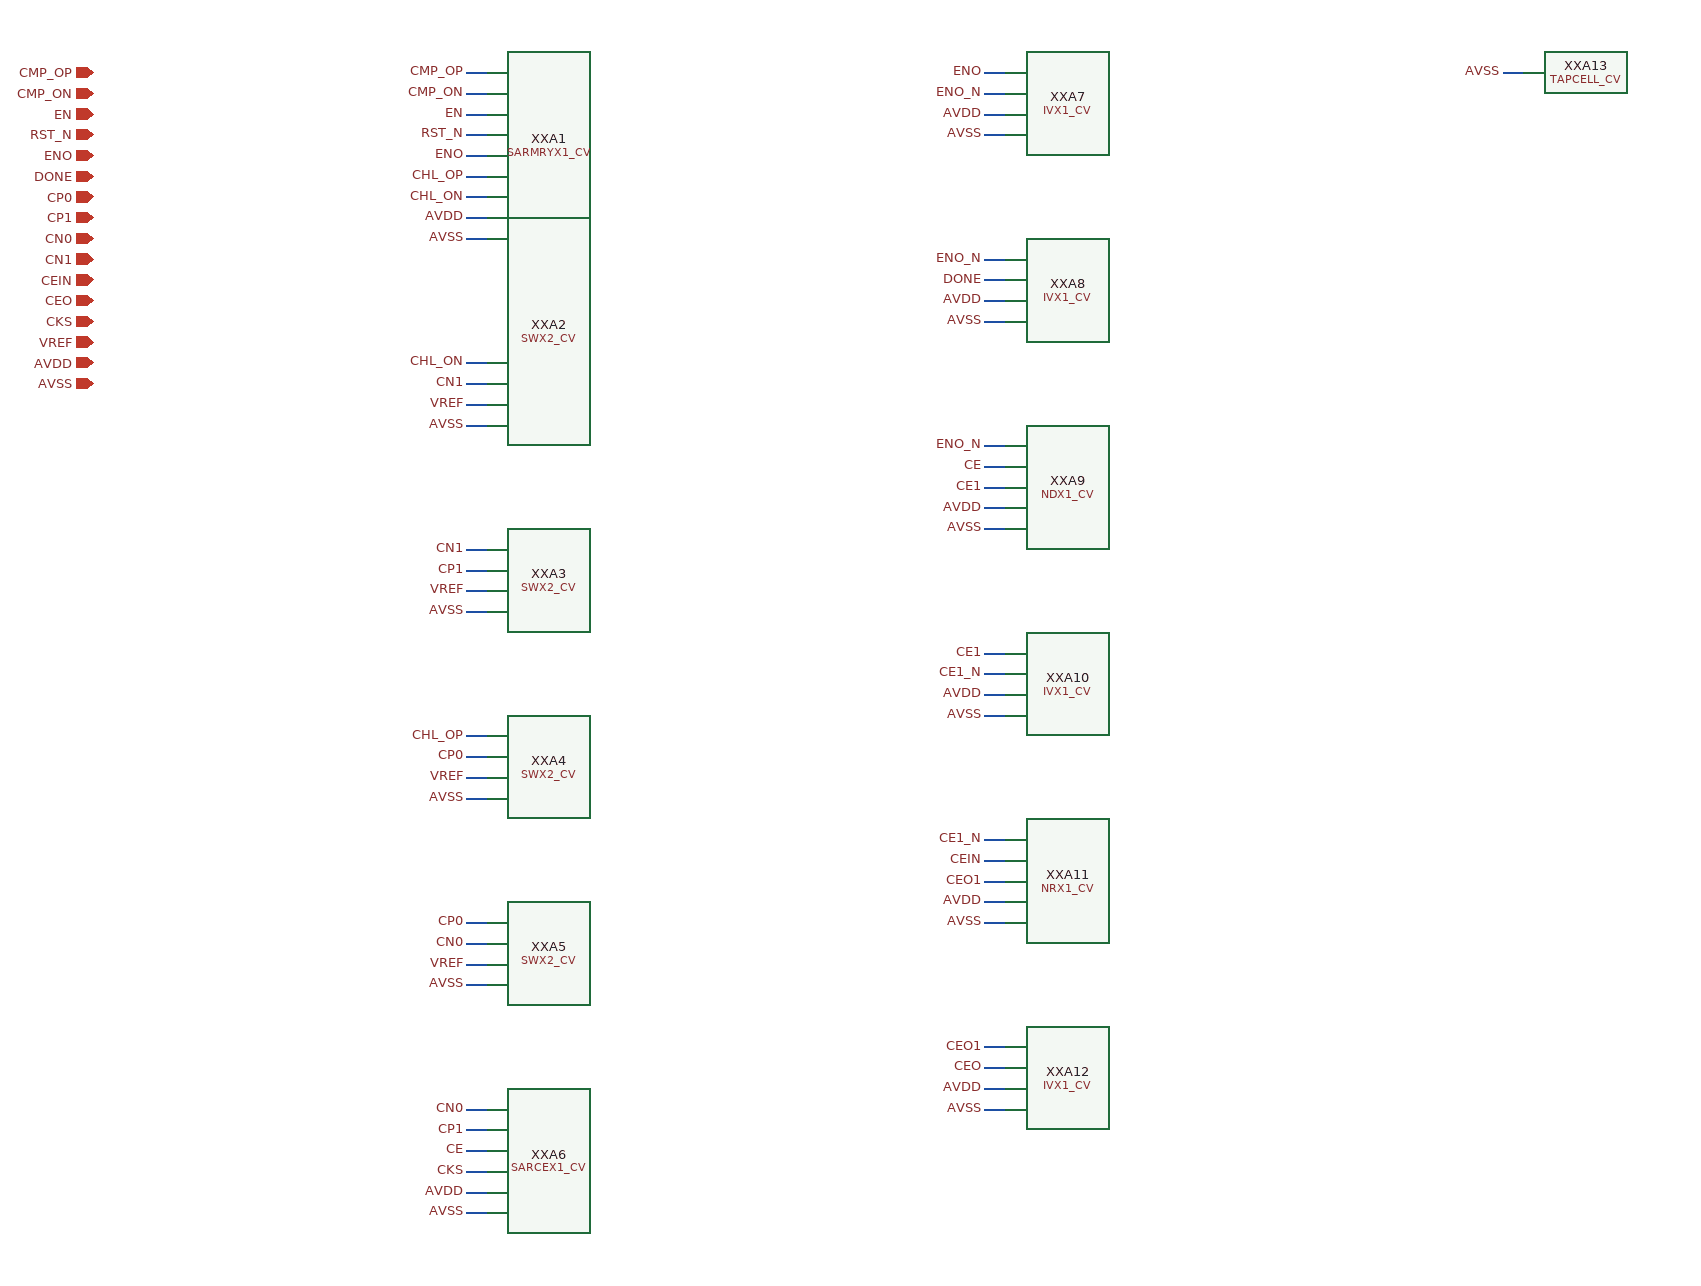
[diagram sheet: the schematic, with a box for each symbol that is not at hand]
v {xschem version=3.0.0 file_version=1.2 }
G {}
K {}
V {}
S {}
E {}
C {devices/iopin.sym} 0 0 0 0 {name=p0 lab=CMP_OP}
C {devices/iopin.sym} 0 20 0 0 {name=p1 lab=CMP_ON}
C {devices/iopin.sym} 0 40 0 0 {name=p2 lab=EN}
C {devices/iopin.sym} 0 60 0 0 {name=p3 lab=RST_N}
C {devices/iopin.sym} 0 80 0 0 {name=p4 lab=ENO}
C {devices/iopin.sym} 0 100 0 0 {name=p5 lab=DONE}
C {devices/iopin.sym} 0 120 0 0 {name=p6 lab=CP0}
C {devices/iopin.sym} 0 140 0 0 {name=p7 lab=CP1}
C {devices/iopin.sym} 0 160 0 0 {name=p8 lab=CN0}
C {devices/iopin.sym} 0 180 0 0 {name=p9 lab=CN1}
C {devices/iopin.sym} 0 200 0 0 {name=p10 lab=CEIN}
C {devices/iopin.sym} 0 220 0 0 {name=p11 lab=CEO}
C {devices/iopin.sym} 0 240 0 0 {name=p12 lab=CKS}
C {devices/iopin.sym} 0 260 0 0 {name=p13 lab=VREF}
C {devices/iopin.sym} 0 280 0 0 {name=p14 lab=AVDD}
C {devices/iopin.sym} 0 300 0 0 {name=p15 lab=AVSS}
C {SAR9B/SARMRYX1_CV.sym} 400 0 0 0 {name=XXA1}
N 360.0 0.0 380.0 0.0 {lab=CMP_OP}
C {devices/lab_pin.sym} 360.0 0.0 0 0 {name=l0 sig_type=std_logic lab=CMP_OP }
N 360.0 20.0 380.0 20.0 {lab=CMP_ON}
C {devices/lab_pin.sym} 360.0 20.0 0 0 {name=l1 sig_type=std_logic lab=CMP_ON }
N 360.0 40.0 380.0 40.0 {lab=EN}
C {devices/lab_pin.sym} 360.0 40.0 0 0 {name=l2 sig_type=std_logic lab=EN }
N 360.0 60.0 380.0 60.0 {lab=RST_N}
C {devices/lab_pin.sym} 360.0 60.0 0 0 {name=l3 sig_type=std_logic lab=RST_N }
N 360.0 80.0 380.0 80.0 {lab=ENO}
C {devices/lab_pin.sym} 360.0 80.0 0 0 {name=l4 sig_type=std_logic lab=ENO }
N 360.0 100.0 380.0 100.0 {lab=CHL_OP}
C {devices/lab_pin.sym} 360.0 100.0 0 0 {name=l5 sig_type=std_logic lab=CHL_OP }
N 360.0 120.0 380.0 120.0 {lab=CHL_ON}
C {devices/lab_pin.sym} 360.0 120.0 0 0 {name=l6 sig_type=std_logic lab=CHL_ON }
N 360.0 140.0 380.0 140.0 {lab=AVDD}
C {devices/lab_pin.sym} 360.0 140.0 0 0 {name=l7 sig_type=std_logic lab=AVDD }
N 360.0 160.0 380.0 160.0 {lab=AVSS}
C {devices/lab_pin.sym} 360.0 160.0 0 0 {name=l8 sig_type=std_logic lab=AVSS }
C {SAR9B/SWX2_CV.sym} 400 280.0 0 0 {name=XXA2}
N 360.0 280.0 380.0 280.0 {lab=CHL_ON}
C {devices/lab_pin.sym} 360.0 280.0 0 0 {name=l9 sig_type=std_logic lab=CHL_ON }
N 360.0 300.0 380.0 300.0 {lab=CN1}
C {devices/lab_pin.sym} 360.0 300.0 0 0 {name=l10 sig_type=std_logic lab=CN1 }
N 360.0 320.0 380.0 320.0 {lab=VREF}
C {devices/lab_pin.sym} 360.0 320.0 0 0 {name=l11 sig_type=std_logic lab=VREF }
N 360.0 340.0 380.0 340.0 {lab=AVSS}
C {devices/lab_pin.sym} 360.0 340.0 0 0 {name=l12 sig_type=std_logic lab=AVSS }
C {SAR9B/SWX2_CV.sym} 400 460.0 0 0 {name=XXA3}
N 360.0 460.0 380.0 460.0 {lab=CN1}
C {devices/lab_pin.sym} 360.0 460.0 0 0 {name=l13 sig_type=std_logic lab=CN1 }
N 360.0 480.0 380.0 480.0 {lab=CP1}
C {devices/lab_pin.sym} 360.0 480.0 0 0 {name=l14 sig_type=std_logic lab=CP1 }
N 360.0 500.0 380.0 500.0 {lab=VREF}
C {devices/lab_pin.sym} 360.0 500.0 0 0 {name=l15 sig_type=std_logic lab=VREF }
N 360.0 520.0 380.0 520.0 {lab=AVSS}
C {devices/lab_pin.sym} 360.0 520.0 0 0 {name=l16 sig_type=std_logic lab=AVSS }
C {SAR9B/SWX2_CV.sym} 400 640.0 0 0 {name=XXA4}
N 360.0 640.0 380.0 640.0 {lab=CHL_OP}
C {devices/lab_pin.sym} 360.0 640.0 0 0 {name=l17 sig_type=std_logic lab=CHL_OP }
N 360.0 660.0 380.0 660.0 {lab=CP0}
C {devices/lab_pin.sym} 360.0 660.0 0 0 {name=l18 sig_type=std_logic lab=CP0 }
N 360.0 680.0 380.0 680.0 {lab=VREF}
C {devices/lab_pin.sym} 360.0 680.0 0 0 {name=l19 sig_type=std_logic lab=VREF }
N 360.0 700.0 380.0 700.0 {lab=AVSS}
C {devices/lab_pin.sym} 360.0 700.0 0 0 {name=l20 sig_type=std_logic lab=AVSS }
C {SAR9B/SWX2_CV.sym} 400 820.0 0 0 {name=XXA5}
N 360.0 820.0 380.0 820.0 {lab=CP0}
C {devices/lab_pin.sym} 360.0 820.0 0 0 {name=l21 sig_type=std_logic lab=CP0 }
N 360.0 840.0 380.0 840.0 {lab=CN0}
C {devices/lab_pin.sym} 360.0 840.0 0 0 {name=l22 sig_type=std_logic lab=CN0 }
N 360.0 860.0 380.0 860.0 {lab=VREF}
C {devices/lab_pin.sym} 360.0 860.0 0 0 {name=l23 sig_type=std_logic lab=VREF }
N 360.0 880.0 380.0 880.0 {lab=AVSS}
C {devices/lab_pin.sym} 360.0 880.0 0 0 {name=l24 sig_type=std_logic lab=AVSS }
C {SAR9B/SARCEX1_CV.sym} 400 1000.0 0 0 {name=XXA6}
N 360.0 1000.0 380.0 1000.0 {lab=CN0}
C {devices/lab_pin.sym} 360.0 1000.0 0 0 {name=l25 sig_type=std_logic lab=CN0 }
N 360.0 1020.0 380.0 1020.0 {lab=CP1}
C {devices/lab_pin.sym} 360.0 1020.0 0 0 {name=l26 sig_type=std_logic lab=CP1 }
N 360.0 1040.0 380.0 1040.0 {lab=CE}
C {devices/lab_pin.sym} 360.0 1040.0 0 0 {name=l27 sig_type=std_logic lab=CE }
N 360.0 1060.0 380.0 1060.0 {lab=CKS}
C {devices/lab_pin.sym} 360.0 1060.0 0 0 {name=l28 sig_type=std_logic lab=CKS }
N 360.0 1080.0 380.0 1080.0 {lab=AVDD}
C {devices/lab_pin.sym} 360.0 1080.0 0 0 {name=l29 sig_type=std_logic lab=AVDD }
N 360.0 1100.0 380.0 1100.0 {lab=AVSS}
C {devices/lab_pin.sym} 360.0 1100.0 0 0 {name=l30 sig_type=std_logic lab=AVSS }
C {SAR9B/IVX1_CV.sym} 900 0 0 0 {name=XXA7}
N 860.0 0.0 880.0 0.0 {lab=ENO}
C {devices/lab_pin.sym} 860.0 0.0 0 0 {name=l31 sig_type=std_logic lab=ENO }
N 860.0 20.0 880.0 20.0 {lab=ENO_N}
C {devices/lab_pin.sym} 860.0 20.0 0 0 {name=l32 sig_type=std_logic lab=ENO_N }
N 860.0 40.0 880.0 40.0 {lab=AVDD}
C {devices/lab_pin.sym} 860.0 40.0 0 0 {name=l33 sig_type=std_logic lab=AVDD }
N 860.0 60.0 880.0 60.0 {lab=AVSS}
C {devices/lab_pin.sym} 860.0 60.0 0 0 {name=l34 sig_type=std_logic lab=AVSS }
C {SAR9B/IVX1_CV.sym} 900 180.0 0 0 {name=XXA8}
N 860.0 180.0 880.0 180.0 {lab=ENO_N}
C {devices/lab_pin.sym} 860.0 180.0 0 0 {name=l35 sig_type=std_logic lab=ENO_N }
N 860.0 200.0 880.0 200.0 {lab=DONE}
C {devices/lab_pin.sym} 860.0 200.0 0 0 {name=l36 sig_type=std_logic lab=DONE }
N 860.0 220.0 880.0 220.0 {lab=AVDD}
C {devices/lab_pin.sym} 860.0 220.0 0 0 {name=l37 sig_type=std_logic lab=AVDD }
N 860.0 240.0 880.0 240.0 {lab=AVSS}
C {devices/lab_pin.sym} 860.0 240.0 0 0 {name=l38 sig_type=std_logic lab=AVSS }
C {SAR9B/NDX1_CV.sym} 900 360.0 0 0 {name=XXA9}
N 860.0 360.0 880.0 360.0 {lab=ENO_N}
C {devices/lab_pin.sym} 860.0 360.0 0 0 {name=l39 sig_type=std_logic lab=ENO_N }
N 860.0 380.0 880.0 380.0 {lab=CE}
C {devices/lab_pin.sym} 860.0 380.0 0 0 {name=l40 sig_type=std_logic lab=CE }
N 860.0 400.0 880.0 400.0 {lab=CE1}
C {devices/lab_pin.sym} 860.0 400.0 0 0 {name=l41 sig_type=std_logic lab=CE1 }
N 860.0 420.0 880.0 420.0 {lab=AVDD}
C {devices/lab_pin.sym} 860.0 420.0 0 0 {name=l42 sig_type=std_logic lab=AVDD }
N 860.0 440.0 880.0 440.0 {lab=AVSS}
C {devices/lab_pin.sym} 860.0 440.0 0 0 {name=l43 sig_type=std_logic lab=AVSS }
C {SAR9B/IVX1_CV.sym} 900 560.0 0 0 {name=XXA10}
N 860.0 560.0 880.0 560.0 {lab=CE1}
C {devices/lab_pin.sym} 860.0 560.0 0 0 {name=l44 sig_type=std_logic lab=CE1 }
N 860.0 580.0 880.0 580.0 {lab=CE1_N}
C {devices/lab_pin.sym} 860.0 580.0 0 0 {name=l45 sig_type=std_logic lab=CE1_N }
N 860.0 600.0 880.0 600.0 {lab=AVDD}
C {devices/lab_pin.sym} 860.0 600.0 0 0 {name=l46 sig_type=std_logic lab=AVDD }
N 860.0 620.0 880.0 620.0 {lab=AVSS}
C {devices/lab_pin.sym} 860.0 620.0 0 0 {name=l47 sig_type=std_logic lab=AVSS }
C {SAR9B/NRX1_CV.sym} 900 740.0 0 0 {name=XXA11}
N 860.0 740.0 880.0 740.0 {lab=CE1_N}
C {devices/lab_pin.sym} 860.0 740.0 0 0 {name=l48 sig_type=std_logic lab=CE1_N }
N 860.0 760.0 880.0 760.0 {lab=CEIN}
C {devices/lab_pin.sym} 860.0 760.0 0 0 {name=l49 sig_type=std_logic lab=CEIN }
N 860.0 780.0 880.0 780.0 {lab=CEO1}
C {devices/lab_pin.sym} 860.0 780.0 0 0 {name=l50 sig_type=std_logic lab=CEO1 }
N 860.0 800.0 880.0 800.0 {lab=AVDD}
C {devices/lab_pin.sym} 860.0 800.0 0 0 {name=l51 sig_type=std_logic lab=AVDD }
N 860.0 820.0 880.0 820.0 {lab=AVSS}
C {devices/lab_pin.sym} 860.0 820.0 0 0 {name=l52 sig_type=std_logic lab=AVSS }
C {SAR9B/IVX1_CV.sym} 900 940.0 0 0 {name=XXA12}
N 860.0 940.0 880.0 940.0 {lab=CEO1}
C {devices/lab_pin.sym} 860.0 940.0 0 0 {name=l53 sig_type=std_logic lab=CEO1 }
N 860.0 960.0 880.0 960.0 {lab=CEO}
C {devices/lab_pin.sym} 860.0 960.0 0 0 {name=l54 sig_type=std_logic lab=CEO }
N 860.0 980.0 880.0 980.0 {lab=AVDD}
C {devices/lab_pin.sym} 860.0 980.0 0 0 {name=l55 sig_type=std_logic lab=AVDD }
N 860.0 1000.0 880.0 1000.0 {lab=AVSS}
C {devices/lab_pin.sym} 860.0 1000.0 0 0 {name=l56 sig_type=std_logic lab=AVSS }
C {SAR9B/TAPCELL_CV.sym} 1400 0 0 0 {name=XXA13}
N 1360.0 0.0 1380.0 0.0 {lab=AVSS}
C {devices/lab_pin.sym} 1360.0 0.0 0 0 {name=l57 sig_type=std_logic lab=AVSS }
